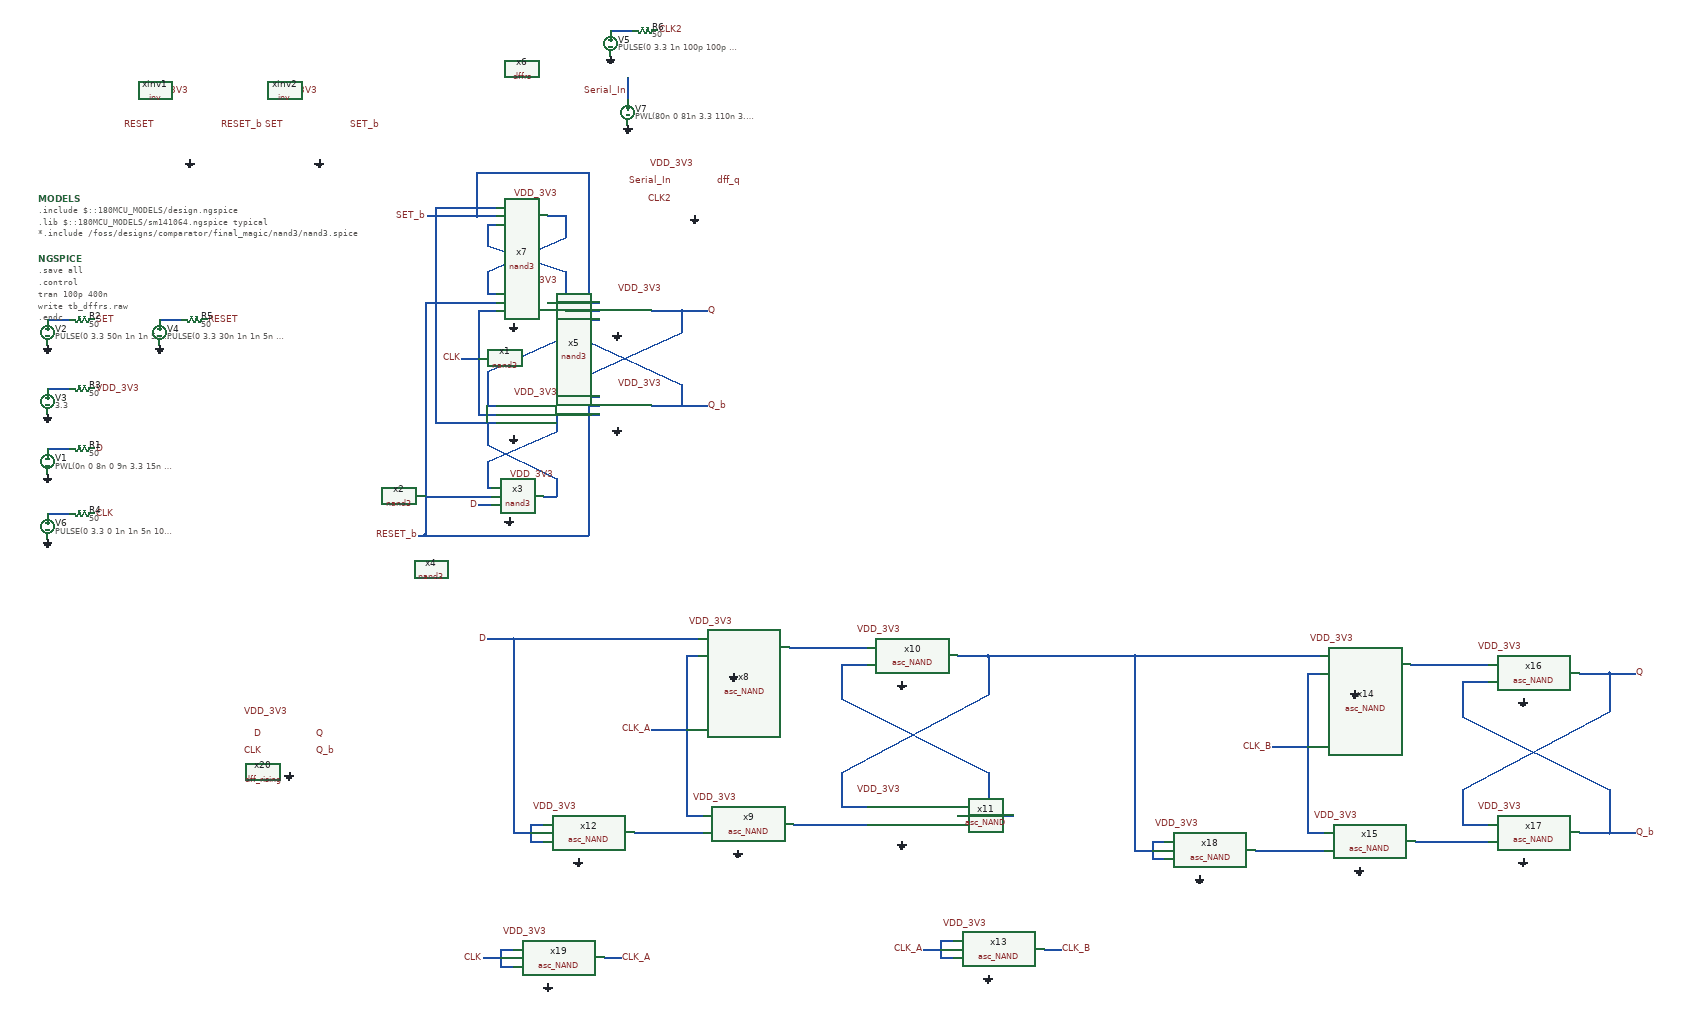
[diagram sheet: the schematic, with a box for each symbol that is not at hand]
v {xschem version=3.4.8RC file_version=1.3}
G {}
K {}
V {}
S {}
F {}
E {}
B 2 2000 -745 2800 -345 {flags=graph
y1=0
y2=3
ypos1=0
ypos2=2
divy=5
subdivy=1
unity=1
x1=-8.7843371e-10
x2=5.9955208e-08
divx=5
subdivx=1
xlabmag=1.0
ylabmag=1.0
node="clk
d
set_b
reset_b
q"
color="4 4 4 4 4"
dataset=-1
unitx=1
logx=0
logy=0
digital=1
autoload=1}
B 2 2000 -1195 2800 -795 {flags=graph
y1=0
ypos1=0
ypos2=2
divy=5
subdivy=1
unity=1
x1=-8.7843371e-10
x2=5.9955208e-08
divx=5
subdivx=1
xlabmag=1.0
ylabmag=1.0
node="clk
serial_in
dff_q
x4.net2
x4.net3
x4.net1"
color="4 4 4 4 4 4"
dataset=-1
unitx=1
logx=0
logy=0
digital=1
y2=2.8}
B 2 2820 -745 3620 -345 {flags=graph
y2=3.5
ypos1=0
ypos2=2
divy=5
subdivy=1
unity=1
x1=-8.7843371e-10
x2=5.9955208e-08
divx=5
subdivx=1
xlabmag=1.0
ylabmag=1.0
node=q
color=4
dataset=-1
unitx=1
logx=0
logy=0
digital=0
autoload=1
y1=-0.1
}
N 1310 -570 1350 -570 {lab=CLK
spice_ignore=true}
N 1350 -230 1380 -230 {lab=D
spice_ignore=true}
N 1600 -660 1630 -660 {lab=Q_b
spice_ignore=true}
N 1600 -660 1600 -610 {lab=Q_b
spice_ignore=true}
N 1600 -610 1820 -510 {lab=Q_b
spice_ignore=true}
N 1820 -510 1820 -460 {lab=Q_b
spice_ignore=true}
N 1820 -680 1820 -630 {lab=Q
spice_ignore=true}
N 1600 -530 1820 -630 {lab=Q
spice_ignore=true}
N 1600 -530 1600 -480 {lab=Q
spice_ignore=true}
N 1600 -480 1630 -480 {lab=Q
spice_ignore=true}
N 1820 -460 1880 -460 {lab=Q_b
spice_ignore=true}
N 1820 -680 1880 -680 {lab=Q
spice_ignore=true}
N 1510 -440 1630 -440 {lab=#net1
spice_ignore=true}
N 1350 -680 1350 -440 {lab=CLK
spice_ignore=true}
N 1370 -460 1390 -460 {lab=#net2
spice_ignore=true}
N 1370 -520 1370 -460 {lab=#net2
spice_ignore=true}
N 1370 -540 1550 -620 {lab=#net2
spice_ignore=true}
N 1370 -540 1370 -520 {lab=#net2
spice_ignore=true}
N 1550 -700 1550 -620 {lab=#net2
spice_ignore=true}
N 1370 -770 1550 -850 {lab=#net3
spice_ignore=true}
N 1370 -770 1370 -720 {lab=#net3
spice_ignore=true}
N 1550 -900 1550 -850 {lab=#net3
spice_ignore=true}
N 1550 -770 1550 -700 {lab=#net2
spice_ignore=true}
N 1370 -830 1550 -770 {lab=#net2
spice_ignore=true}
N 1370 -880 1370 -830 {lab=#net2
spice_ignore=true}
N 1370 -880 1390 -880 {lab=#net2
spice_ignore=true}
N 1350 -680 1390 -680 {lab=CLK
spice_ignore=true}
N 1350 -440 1390 -440 {lab=CLK
spice_ignore=true}
N 1250 -920 1390 -920 {lab=#net4
spice_ignore=true}
N 1250 -920 1250 -420 {lab=#net4
spice_ignore=true}
N 1250 -420 1390 -420 {lab=#net4
spice_ignore=true}
N 1370 -420 1370 -370 {lab=#net4
spice_ignore=true}
N 1370 -370 1530 -290 {lab=#net4
spice_ignore=true}
N 1530 -290 1530 -250 {lab=#net4
spice_ignore=true}
N 1370 -270 1380 -270 {lab=#net1
spice_ignore=true}
N 1370 -330 1370 -270 {lab=#net1
spice_ignore=true}
N 1370 -330 1530 -400 {lab=#net1
spice_ignore=true}
N 1530 -440 1530 -400 {lab=#net1
spice_ignore=true}
N 1370 -720 1390 -720 {lab=#net3
spice_ignore=true}
N 1750 -680 1820 -680 {lab=Q
spice_ignore=true}
N 1750 -460 1820 -460 {lab=Q_b
spice_ignore=true}
N 1510 -900 1550 -900 {lab=#net3
spice_ignore=true}
N 1500 -250 1530 -250 {lab=#net4
spice_ignore=true}
N 1510 -700 1550 -700 {lab=#net2
spice_ignore=true}
N 1550 -680 1630 -680 {lab=#net2
spice_ignore=true}
N 1605 -700 1630 -700 {lab=SET_b
spice_ignore=true}
N 1605 -1000 1605 -700 {lab=SET_b
spice_ignore=true}
N 1345 -1000 1605 -1000 {lab=SET_b
spice_ignore=true}
N 1345 -1000 1345 -900 {lab=SET_b
spice_ignore=true}
N 1345 -900 1390 -900 {lab=SET_b
spice_ignore=true}
N 1230 -900 1345 -900 {lab=SET_b
spice_ignore=true}
N 1225 -700 1390 -700 {lab=RESET_b
spice_ignore=true}
N 1225 -700 1225 -160 {lab=RESET_b
spice_ignore=true}
N 1210 -160 1225 -160 {lab=RESET_b
spice_ignore=true}
N 1225 -250 1380 -250 {lab=RESET_b
spice_ignore=true}
N 1605 -460 1630 -460 {lab=RESET_b
spice_ignore=true}
N 1605 -460 1605 -160 {lab=RESET_b
spice_ignore=true}
N 1225 -160 1605 -160 {lab=RESET_b
spice_ignore=true}
N 350 -210 400 -210 {lab=#net1}
N 350 -360 400 -360 {lab=#net2}
N 350 -500 400 -500 {lab=#net3}
N 350 -660 400 -660 {lab=#net4}
N 610 -660 660 -660 {lab=#net5}
N 1655 -1330 1705 -1330 {lab=#net6}
N 1695 -1220 1695 -1170 {lab=Serial_In}
N 1830 120 1860 120 {lab=CLK_A
spice_ignore=true}
N 1830 120 1830 490 {lab=CLK_A
spice_ignore=true}
N 1830 490 1870 490 {lab=CLK_A
spice_ignore=true}
N 1710 530 1870 530 {lab=#net7
spice_ignore=true}
N 2080 510 2250 510 {lab=#net8
spice_ignore=true}
N 2070 100 2250 100 {lab=#net9
spice_ignore=true}
N 2190 470 2250 470 {lab=#net10
spice_ignore=true}
N 2190 390 2190 470 {lab=#net10
spice_ignore=true}
N 2190 390 2530 210 {lab=#net10
spice_ignore=true}
N 2530 120 2530 210 {lab=#net10
spice_ignore=true}
N 2460 120 2530 120 {lab=#net10
spice_ignore=true}
N 2190 140 2250 140 {lab=#net11
spice_ignore=true}
N 2190 140 2190 220 {lab=#net11
spice_ignore=true}
N 2190 220 2530 390 {lab=#net11
spice_ignore=true}
N 2530 390 2530 490 {lab=#net11
spice_ignore=true}
N 2460 490 2530 490 {lab=#net11
spice_ignore=true}
N 2530 490 2590 490 {lab=#net11
spice_ignore=true}
N 2530 120 2590 120 {lab=#net10
spice_ignore=true}
N 1470 510 1500 510 {lab=D
spice_ignore=true}
N 1470 510 1470 550 {lab=D
spice_ignore=true}
N 1470 550 1500 550 {lab=D
spice_ignore=true}
N 1430 530 1470 530 {lab=D
spice_ignore=true}
N 1430 80 1860 80 {lab=D
spice_ignore=true}
N 1430 80 1430 530 {lab=D
spice_ignore=true}
N 1370 80 1430 80 {lab=D
spice_ignore=true}
N 1750 290 1830 290 {lab=CLK_A
spice_ignore=true}
N 2420 780 2450 780 {lab=CLK_A
spice_ignore=true}
N 2420 780 2420 820 {lab=CLK_A
spice_ignore=true}
N 2420 820 2450 820 {lab=CLK_A
spice_ignore=true}
N 2380 800 2420 800 {lab=CLK_A
spice_ignore=true}
N 2660 800 2700 800 {lab=CLK_B
spice_ignore=true}
N 3270 160 3300 160 {lab=CLK_B
spice_ignore=true}
N 3270 160 3270 530 {lab=CLK_B
spice_ignore=true}
N 3270 530 3310 530 {lab=CLK_B
spice_ignore=true}
N 3150 570 3310 570 {lab=#net12
spice_ignore=true}
N 3520 550 3690 550 {lab=#net13
spice_ignore=true}
N 3510 140 3690 140 {lab=#net14
spice_ignore=true}
N 3630 510 3690 510 {lab=Q
spice_ignore=true}
N 3630 430 3630 510 {lab=Q
spice_ignore=true}
N 3630 430 3970 250 {lab=Q
spice_ignore=true}
N 3970 160 3970 250 {lab=Q
spice_ignore=true}
N 3900 160 3970 160 {lab=Q
spice_ignore=true}
N 3630 180 3690 180 {lab=Q_b
spice_ignore=true}
N 3630 180 3630 260 {lab=Q_b
spice_ignore=true}
N 3630 260 3970 430 {lab=Q_b
spice_ignore=true}
N 3970 430 3970 530 {lab=Q_b
spice_ignore=true}
N 3900 530 3970 530 {lab=Q_b
spice_ignore=true}
N 3970 530 4030 530 {lab=Q_b
spice_ignore=true}
N 3970 160 4030 160 {lab=Q
spice_ignore=true}
N 2910 550 2940 550 {lab=#net10
spice_ignore=true}
N 2910 550 2910 590 {lab=#net10
spice_ignore=true}
N 2910 590 2940 590 {lab=#net10
spice_ignore=true}
N 2870 570 2910 570 {lab=#net10
spice_ignore=true}
N 2870 120 3300 120 {lab=#net10
spice_ignore=true}
N 2870 120 2870 570 {lab=#net10
spice_ignore=true}
N 2810 120 2870 120 {lab=#net10
spice_ignore=true}
N 3190 330 3270 330 {lab=CLK_B
spice_ignore=true}
N 2590 120 2810 120 {lab=#net10
spice_ignore=true}
N 1400 800 1430 800 {lab=CLK
spice_ignore=true}
N 1400 800 1400 840 {lab=CLK
spice_ignore=true}
N 1400 840 1430 840 {lab=CLK
spice_ignore=true}
N 1360 820 1400 820 {lab=CLK
spice_ignore=true}
N 1640 820 1680 820 {lab=CLK_A
spice_ignore=true}
C {devices/code_shown.sym} 330 -940 0 0 {name=MODELS only_toplevel=true
format="tcleval( @value )"
value="
.include $::180MCU_MODELS/design.ngspice
.lib $::180MCU_MODELS/sm141064.ngspice typical
*.include /foss/designs/comparator/final_magic/nand3/nand3.spice
"}
C {code_shown.sym} 330 -800 0 0 {name=NGSPICE only_toplevel=true value=
".save all
.control
tran 100p 400n
write tb_dffrs.raw
.endc"}
C {devices/launcher.sym} 660 -800 0 0 {name=h3
descr="save, netlist & simulate"
tclcommand="xschem save; xschem netlist; xschem simulate"}
C {launcher.sym} 660 -755 0 0 {name=h5 
descr="load ngspice waves" 
tclcommand="
xschem raw_read $netlist_dir/tb_dffrs.raw tran; xschem redraw
"
}
C {vsource.sym} 350 -180 0 0 {name=V6 value="PULSE(0 3.3 0 1n 1n 5n 10n)" savecurrent=false}
C {lab_pin.sym} 460 -210 0 1 {name=p20 sig_type=std_logic lab=CLK}
C {gnd.sym} 350 -150 0 0 {name=l14 lab=GND}
C {res.sym} 430 -210 1 0 {name=R4
value=50
footprint=1206
device=resistor
m=1}
C {vsource.sym} 350 -330 0 0 {name=V1 value="PWL(0n 0 8n 0 9n 3.3 15n 3.3 16n 0 34n 0 35n 3.3 40n 3.3 41n 0 60n 0)" savecurrent=false}
C {lab_pin.sym} 460 -360 0 1 {name=p10 sig_type=std_logic lab=D}
C {gnd.sym} 350 -300 0 0 {name=l1 lab=GND}
C {res.sym} 430 -360 1 0 {name=R1
value=50
footprint=1206
device=resistor
m=1}
C {vsource.sym} 350 -470 0 0 {name=V3 value=3.3 savecurrent=false}
C {lab_pin.sym} 460 -500 0 1 {name=p23 sig_type=std_logic lab=VDD_3V3}
C {gnd.sym} 350 -440 0 0 {name=l4 lab=GND}
C {res.sym} 430 -500 1 0 {name=R3
value=50
footprint=1206
device=resistor
m=1}
C {vsource.sym} 350 -630 0 0 {name=V2 value="PULSE(0 3.3 50n 1n 1n 5n 100n)" savecurrent=false}
C {lab_pin.sym} 460 -660 0 1 {name=p28 sig_type=std_logic lab=SET}
C {gnd.sym} 350 -600 0 0 {name=l2 lab=GND}
C {res.sym} 430 -660 1 0 {name=R2
value=50
footprint=1206
device=resistor
m=1}
C {vsource.sym} 610 -630 0 0 {name=V4 value="PULSE(0 3.3 30n 1n 1n 5n 100n)" savecurrent=false}
C {lab_pin.sym} 720 -660 0 1 {name=p29 sig_type=std_logic lab=RESET}
C {gnd.sym} 610 -600 0 0 {name=l3 lab=GND}
C {res.sym} 690 -660 1 0 {name=R5
value=50
footprint=1206
device=resistor
m=1}
C {lab_pin.sym} 1420 -300 0 1 {name=p30 sig_type=std_logic lab=VDD_3V3
spice_ignore=true}
C {gnd.sym} 1420 -200 0 0 {name=l6 lab=GND
spice_ignore=true}
C {lab_pin.sym} 1350 -230 0 0 {name=p31 sig_type=std_logic lab=D
spice_ignore=true}
C {lab_pin.sym} 1880 -680 0 1 {name=p32 sig_type=std_logic lab=Q
spice_ignore=true}
C {lab_pin.sym} 1310 -570 0 0 {name=p33 sig_type=std_logic lab=CLK
spice_ignore=true}
C {gnd.sym} 1430 -390 0 0 {name=l8 lab=GND
spice_ignore=true}
C {gnd.sym} 1670 -410 0 0 {name=l9 lab=GND
spice_ignore=true}
C {gnd.sym} 1670 -630 0 0 {name=l10 lab=GND
spice_ignore=true}
C {gnd.sym} 1430 -650 0 0 {name=l11 lab=GND
spice_ignore=true}
C {gnd.sym} 1430 -850 0 0 {name=l12 lab=GND
spice_ignore=true}
C {lab_pin.sym} 1430 -490 0 1 {name=p1 sig_type=std_logic lab=VDD_3V3
spice_ignore=true}
C {lab_pin.sym} 1670 -510 0 1 {name=p2 sig_type=std_logic lab=VDD_3V3
spice_ignore=true}
C {lab_pin.sym} 1670 -730 0 1 {name=p3 sig_type=std_logic lab=VDD_3V3
spice_ignore=true}
C {lab_pin.sym} 1430 -750 0 1 {name=p4 sig_type=std_logic lab=VDD_3V3
spice_ignore=true}
C {lab_pin.sym} 1430 -950 0 1 {name=p5 sig_type=std_logic lab=VDD_3V3
spice_ignore=true}
C {lab_pin.sym} 1880 -460 0 1 {name=p6 sig_type=std_logic lab=Q_b
spice_ignore=true}
C {lab_pin.sym} 1850 -1020 0 0 {name=p9 sig_type=std_logic lab=VDD_3V3
spice_ignore=true}
C {gnd.sym} 1850 -900 0 0 {name=l13 lab=GND
spice_ignore=true}
C {lab_pin.sym} 1800 -940 0 0 {name=p11 sig_type=std_logic lab=CLK2
spice_ignore=true}
C {lab_pin.sym} 1800 -980 0 0 {name=p12 sig_type=std_logic lab=Serial_In
spice_ignore=true}
C {lab_pin.sym} 1900 -980 0 1 {name=p13 sig_type=std_logic lab=dff_q
spice_ignore=true}
C {vsource.sym} 1655 -1300 0 0 {name=V5 value="PULSE(0 3.3 1n 100p 100p 10.1n 20n)" savecurrent=false}
C {lab_pin.sym} 1765 -1330 0 1 {name=p14 sig_type=std_logic lab=CLK2}
C {gnd.sym} 1655 -1270 0 0 {name=l15 lab=GND}
C {res.sym} 1735 -1330 1 0 {name=R6
value=50
footprint=1206
device=resistor
m=1}
C {vsource.sym} 1695 -1140 0 1 {name=V7 value="PWL(80n 0 81n 3.3 110n 3.3 111n 0 180n 0 181n 3.3 220n 3.3 221n 0)" savecurrent=false}
C {gnd.sym} 1695 -1110 0 0 {name=l16 lab=GND}
C {lab_wire.sym} 1695 -1190 0 0 {name=p15 sig_type=std_logic lab=Serial_In}
C {lab_pin.sym} 600 -1110 0 0 {name=p16 sig_type=std_logic lab=RESET}
C {lab_pin.sym} 900 -1110 0 0 {name=p17 sig_type=std_logic lab=SET}
C {lab_pin.sym} 750 -1110 0 1 {name=p18 sig_type=std_logic lab=RESET_b}
C {lab_pin.sym} 1050 -1110 0 1 {name=p19 sig_type=std_logic lab=SET_b}
C {lab_pin.sym} 680 -1190 3 1 {name=p21 sig_type=std_logic lab=VDD_3V3}
C {lab_pin.sym} 980 -1190 3 1 {name=p22 sig_type=std_logic lab=VDD_3V3}
C {gnd.sym} 680 -1030 0 0 {name=l17 lab=GND}
C {gnd.sym} 980 -1030 0 0 {name=l18 lab=GND}
C {lab_pin.sym} 1210 -160 0 0 {name=p7 sig_type=std_logic lab=RESET_b
spice_ignore=true}
C {lab_pin.sym} 1230 -900 0 0 {name=p8 sig_type=std_logic lab=SET_b
spice_ignore=true}
C {Analog/schematics/1_readout/slopedetector/dffrs/nand3.sym} 1250 -730 0 0 {name=x7
spice_ignore=true}
C {Analog/schematics/1_readout/slopedetector/dffrs/nand3.sym} 1250 -530 0 0 {name=x1
spice_ignore=true}
C {Analog/schematics/1_readout/slopedetector/dffrs/nand3.sym} 1250 -270 0 0 {name=x2
spice_ignore=true}
C {Analog/schematics/1_readout/slopedetector/dffrs/nand3.sym} 1490 -290 0 0 {name=x3
spice_ignore=true}
C {Analog/schematics/1_readout/slopedetector/dffrs/nand3.sym} 1240 -80 0 0 {name=x4
spice_ignore=true}
C {Analog/schematics/1_readout/slopedetector/dffrs/nand3.sym} 1490 -510 0 0 {name=x5
spice_ignore=true}
C {Analog/schematics/3_comparator/inv.sym} 600 -1190 0 0 {name=xinv1}
C {Analog/schematics/3_comparator/inv.sym} 900 -1190 0 0 {name=xinv2}
C {Analog/schematics/1_readout/slopedetector/dffrs/dffrs.sym} 1690 -940 0 0 {name=x6
spice_ignore=true}
C {Analog/schematics/1_readout/slopedetector/nand/asc_NAND.sym} 1940 100 0 0 {name=x8
spice_ignore=true}
C {lab_pin.sym} 1940 40 3 1 {name=p24 sig_type=std_logic lab=VDD_3V3
spice_ignore=true}
C {gnd.sym} 1940 160 0 0 {name=l5 lab=GND
spice_ignore=true}
C {Analog/schematics/1_readout/slopedetector/nand/asc_NAND.sym} 1950 510 0 0 {name=x9
spice_ignore=true}
C {lab_pin.sym} 1950 450 3 1 {name=p25 sig_type=std_logic lab=VDD_3V3
spice_ignore=true}
C {gnd.sym} 1950 570 0 0 {name=l7 lab=GND
spice_ignore=true}
C {Analog/schematics/1_readout/slopedetector/nand/asc_NAND.sym} 2330 120 0 0 {name=x10
spice_ignore=true}
C {lab_pin.sym} 2330 60 3 1 {name=p26 sig_type=std_logic lab=VDD_3V3
spice_ignore=true}
C {gnd.sym} 2330 180 0 0 {name=l19 lab=GND
spice_ignore=true}
C {Analog/schematics/1_readout/slopedetector/nand/asc_NAND.sym} 2330 490 0 0 {name=x11
spice_ignore=true}
C {lab_pin.sym} 2330 430 3 1 {name=p27 sig_type=std_logic lab=VDD_3V3
spice_ignore=true}
C {gnd.sym} 2330 550 0 0 {name=l20 lab=GND
spice_ignore=true}
C {Analog/schematics/1_readout/slopedetector/nand/asc_NAND.sym} 1580 530 0 0 {name=x12
spice_ignore=true}
C {lab_pin.sym} 1580 470 3 1 {name=p34 sig_type=std_logic lab=VDD_3V3
spice_ignore=true}
C {gnd.sym} 1580 590 0 0 {name=l21 lab=GND
spice_ignore=true}
C {lab_pin.sym} 1370 80 0 0 {name=p36 sig_type=std_logic lab=D
spice_ignore=true}
C {lab_pin.sym} 2380 800 0 0 {name=p39 sig_type=std_logic lab=CLK_A
spice_ignore=true}
C {Analog/schematics/1_readout/slopedetector/nand/asc_NAND.sym} 2530 800 0 0 {name=x13
spice_ignore=true}
C {lab_pin.sym} 2530 740 3 1 {name=p40 sig_type=std_logic lab=VDD_3V3
spice_ignore=true}
C {gnd.sym} 2530 860 0 0 {name=l22 lab=GND
spice_ignore=true}
C {lab_pin.sym} 2700 800 0 1 {name=p41 sig_type=std_logic lab=CLK_B
spice_ignore=true}
C {Analog/schematics/1_readout/slopedetector/nand/asc_NAND.sym} 3380 140 0 0 {name=x14
spice_ignore=true}
C {lab_pin.sym} 3380 80 3 1 {name=p42 sig_type=std_logic lab=VDD_3V3
spice_ignore=true}
C {gnd.sym} 3380 200 0 0 {name=l23 lab=GND
spice_ignore=true}
C {Analog/schematics/1_readout/slopedetector/nand/asc_NAND.sym} 3390 550 0 0 {name=x15
spice_ignore=true}
C {lab_pin.sym} 3390 490 3 1 {name=p43 sig_type=std_logic lab=VDD_3V3
spice_ignore=true}
C {gnd.sym} 3390 610 0 0 {name=l24 lab=GND
spice_ignore=true}
C {Analog/schematics/1_readout/slopedetector/nand/asc_NAND.sym} 3770 160 0 0 {name=x16
spice_ignore=true}
C {lab_pin.sym} 3770 100 3 1 {name=p44 sig_type=std_logic lab=VDD_3V3
spice_ignore=true}
C {gnd.sym} 3770 220 0 0 {name=l25 lab=GND
spice_ignore=true}
C {Analog/schematics/1_readout/slopedetector/nand/asc_NAND.sym} 3770 530 0 0 {name=x17
spice_ignore=true}
C {lab_pin.sym} 3770 470 3 1 {name=p45 sig_type=std_logic lab=VDD_3V3
spice_ignore=true}
C {gnd.sym} 3770 590 0 0 {name=l26 lab=GND
spice_ignore=true}
C {Analog/schematics/1_readout/slopedetector/nand/asc_NAND.sym} 3020 570 0 0 {name=x18
spice_ignore=true}
C {lab_pin.sym} 3020 510 3 1 {name=p46 sig_type=std_logic lab=VDD_3V3
spice_ignore=true}
C {gnd.sym} 3020 630 0 0 {name=l27 lab=GND
spice_ignore=true}
C {lab_pin.sym} 4030 160 0 1 {name=p49 sig_type=std_logic lab=Q
spice_ignore=true}
C {lab_pin.sym} 4030 530 0 1 {name=p50 sig_type=std_logic lab=Q_b
spice_ignore=true}
C {lab_pin.sym} 3190 330 0 0 {name=p37 sig_type=std_logic lab=CLK_B
spice_ignore=true}
C {lab_pin.sym} 1360 820 0 0 {name=p38 sig_type=std_logic lab=CLK
spice_ignore=true}
C {Analog/schematics/1_readout/slopedetector/nand/asc_NAND.sym} 1510 820 0 0 {name=x19
spice_ignore=true}
C {lab_pin.sym} 1510 760 3 1 {name=p47 sig_type=std_logic lab=VDD_3V3
spice_ignore=true}
C {gnd.sym} 1510 880 0 0 {name=l28 lab=GND
spice_ignore=true}
C {lab_pin.sym} 1680 820 0 1 {name=p48 sig_type=std_logic lab=CLK_A
spice_ignore=true}
C {lab_pin.sym} 1750 290 0 0 {name=p35 sig_type=std_logic lab=CLK_A
spice_ignore=true}
C {Analog/schematics/1_readout/slopedetector/dff_risingedge/dff_rising.sym} 850 390 0 0 {name=x20}
C {lab_pin.sym} 850 300 0 0 {name=p51 sig_type=std_logic lab=D}
C {lab_pin.sym} 850 340 0 0 {name=p52 sig_type=std_logic lab=CLK}
C {gnd.sym} 910 390 0 0 {name=l29 lab=GND}
C {lab_pin.sym} 910 250 3 1 {name=p53 sig_type=std_logic lab=VDD_3V3}
C {lab_pin.sym} 970 300 0 1 {name=p54 sig_type=std_logic lab=Q}
C {lab_pin.sym} 970 340 0 1 {name=p56 sig_type=std_logic lab=Q_b}
